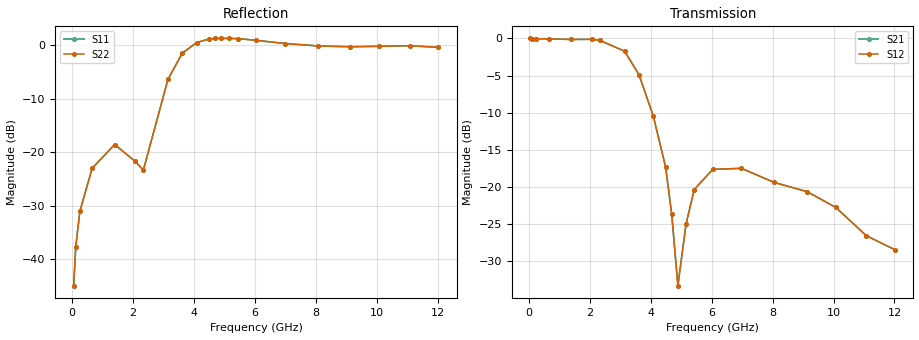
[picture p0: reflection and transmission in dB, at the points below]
!	AVX	Thin Film Operation  Date:	April 2014
!	Description: 0402 SIZE LOW PASS FILTER
!	Part Number: LP0402N2442ANTR
!	50MHz	-  12GHz
!	Serial Measurements
#	MHZ	S	dB	R	50
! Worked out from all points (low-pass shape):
!   179 points, 50 MHz to 12.02 GHz, reference 50 ohm
!   highest |S21| = -0.01 dB at 50 MHz (marker M1); lowest = -33.3 dB at 4.892 GHz (marker M2)
!   |S21| within 3 dB of the highest: start of sweep to 3.377 GHz
!   lowest |S11| = -45.0 dB at 50 MHz (marker M3), VSWR 1.01, Z = 50.5 - j0.281 ohm
!   |S11| at or under -10 dB: start of sweep to 2.924 GHz
!   |S22| runs from -45.0 to 1.2 dB; largest |S21 - S12| = 0.00012
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50  -44.98 -29.5  -0.01 -1.1  -0.00 -1.1  -44.98 -29.5
117.25  -37.76 -68.0  -0.03 -2.6  -0.03 -2.6  -37.76 -68.0
251.75  -31.11 -85.5  -0.05 -5.3  -0.05 -5.3  -31.11 -85.5
655.25  -23.05 -108.2  -0.07 -13.9  -0.07 -13.9  -23.05 -108.2
1395  -18.60 -139.3  -0.15 -30.2  -0.15 -30.2  -18.60 -139.3
2067.5  -21.74 -158.5  -0.13 -47.6  -0.13 -47.6  -21.74 -158.5
2336.5  -23.39 -154.3  -0.28 -55.0  -0.28 -55.0  -23.39 -154.3
3143.5  -6.43 -92.4  -1.73 -87.7  -1.73 -87.7  -6.43 -92.4
3614.25  -1.53 -121.8  -4.88 -113.7  -4.88 -113.7  -1.53 -121.8
4085  0.46 -158.4  -10.47 -137.6  -10.47 -137.6  0.46 -158.4
4488.5  1.11 173.0  -17.30 -154.3  -17.30 -154.3  1.11 173.0
4690.25  1.23 161.2  -23.70 -160.4  -23.70 -160.4  1.23 161.2
4892  1.24 150.0  -33.30 -166.1  -33.30 -166.1  1.24 150.0
5161  1.23 135.3  -24.97 -168.2  -24.97 -168.2  1.23 135.3
5430  1.19 122.1  -20.35 -116.0  -20.35 -116.0  1.19 122.1
6035.25  0.88 94.3  -17.64 -40.8  -17.64 -40.8  0.88 94.3
6976.75  0.28 55.7  -17.50 -49.6  -17.50 -49.6  0.28 55.7
8052.75  -0.17 18.9  -19.40 -53.7  -19.40 -53.7  -0.17 18.9
9128.75  -0.33 -16.1  -20.63 -52.5  -20.63 -52.5  -0.33 -16.1
10070.25  -0.24 -43.2  -22.75 -64.7  -22.75 -64.7  -0.24 -43.2
11079  -0.13 -71.9  -26.58 -65.8  -26.58 -65.8  -0.13 -71.9
12020.5  -0.44 -94.1  -28.47 -65.1  -28.47 -65.1  -0.44 -94.1
